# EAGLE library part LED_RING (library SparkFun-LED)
16 LED Ring COM-10595 http://dlnmh9ip6v2uc.cloudfront.net/datasheets/Components/LED/Top-Up%20LED%20Ring%20LED-CCL-A.pdf

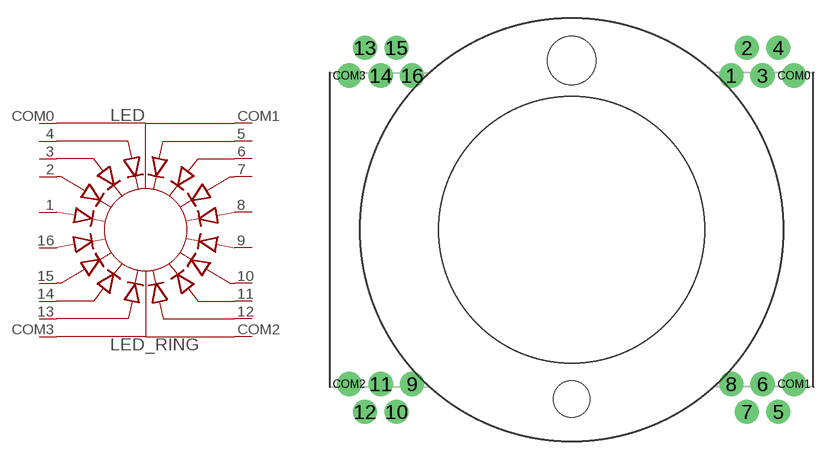
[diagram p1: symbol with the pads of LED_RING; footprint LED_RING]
Designator prefix LED

## LED_RING  [LED_RING]
1  1  pas
2  2  pas
3  3  pas
4  4  pas
5  5  pas
6  6  pas
7  7  pas
8  8  pas
9  9  pas
10  10  pas
11  11  pas
12  12  pas
13  13  pas
14  14  pas
15  15  pas
16  16  pas
COM0  COM0  pas
COM1  COM1  pas
COM2  COM2  pas
COM3  COM3  pas

## Footprint LED_RING (pad centres in mm)
LED Ring http://dlnmh9ip6v2uc.cloudfront.net/datasheets/Components/LED/Top-Up%20LED%20Ring%20LED-CCL-A.pdf
drill 1.2 pad 2: 1 13.2,12.75; 2 14.5,15.05; 3 15.8,12.75; 4 17.1,15.05; 5 17.1,-15.05; 6 15.8,-12.75; 7 14.5,-15.05; 8 13.2,-12.75; 9 -13.2,-12.75; 10 -14.5,-15.05; 11 -15.8,-12.75; 12 -17.1,-15.05; 13 -17.1,15.05; 14 -15.8,12.75; 15 -14.5,15.05; 16 -13.2,12.75; COM0 18.4,12.75; COM1 18.4,-12.75; COM2 -18.4,-12.75; COM3 -18.4,12.75
hole 4 at 0,14
hole 3 at 0,-14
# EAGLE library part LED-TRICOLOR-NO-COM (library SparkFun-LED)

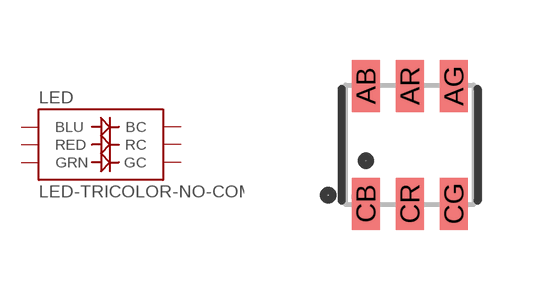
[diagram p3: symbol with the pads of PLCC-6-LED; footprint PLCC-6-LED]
Designator prefix LED

## LED-TRICOLOR-NO-COMPLCC-6-SMD (PROD_ID: DIO-12113)  [PLCC-6-LED]
AB  BLU
AG  GRN
AR  RED
CB  BC
CG  GC
CR  RC

## Footprint PLCC-6-LED (pad centres in mm)
smd 0.7 x 1.3: AB -1.1,1.475; AG 1.1,1.475; AR 0,1.475; CB -1.1,-1.475; CG 1.1,-1.475; CR 0,-1.475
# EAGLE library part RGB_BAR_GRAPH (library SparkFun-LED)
SparkFun 48 Segment RGB Bar Graph - Common Anode

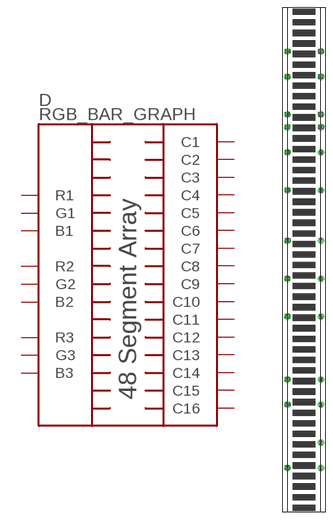
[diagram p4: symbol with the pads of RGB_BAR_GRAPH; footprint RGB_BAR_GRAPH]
Designator prefix D

## RGB_BAR_GRAPHCA (PROD_ID: COM-13520)  [RGB_BAR_GRAPH]
1  C1
2  G3
3  C3
4  C4
5  C6
6  B2
7  G1
8  C10
9  R1
10  C13
11  C14
12  C16
13  R3
14  B3
15  C15
16  G2
17  R2
18  C12
19  C11
20  C9
21  C8
22  C7
23  C5
24  B1
25  C2

## Footprint RGB_BAR_GRAPH (pad centres in mm)
drill 0.8: 1 3.36,-41.9; 2 3.36,-36.82; 3 3.36,-29.2; 4 3.36,-24.12; 5 3.36,-11.42; 6 3.36,-3.8; 7 3.36,3.82; 8 3.36,13.98; 9 3.36,21.6; 10 3.36,26.68; 11 3.36,29.22; 12 3.36,36.84; 13 3.36,41.92; 14 -3.36,41.92; 15 -3.36,36.84; 16 -3.36,29.22; 17 -3.36,26.68; 18 -3.36,21.6; 19 -3.36,13.98; 20 -3.36,3.82; 21 -3.36,-3.8; 22 -3.36,-11.42; 23 -3.36,-24.12; 24 -3.36,-29.2; 25 -3.36,-41.9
